VERSION 5.8 ;
BUSBITCHARS "[]" ;
DIVIDERCHAR "/" ;
UNITS
  DATABASE MICRONS 1000 ;
END UNITS
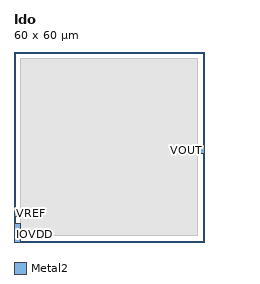
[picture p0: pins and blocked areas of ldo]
MACRO ldo
  CLASS BLOCK ;
  ORIGIN 0 0 ;
  FOREIGN ldo 0 0 ;
  SIZE 60.000 BY 60.000 ;
  SYMMETRY X Y R90 ;
  PIN IOVDD  DIRECTION INOUT ; USE POWER  ; PORT LAYER Metal2 ; RECT 0 0 2 2 ; END END IOVDD
  PIN VSS    DIRECTION INOUT ; USE GROUND ; PORT LAYER Metal2 ; RECT 0 4 2 6 ; END END VSS
  PIN VREF   DIRECTION INPUT ; USE SIGNAL ; PORT LAYER Metal2 ; RECT 0 8 2 10 ; END END VREF
  PIN VOUT   DIRECTION OUTPUT; USE SIGNAL ; PORT LAYER Metal2 ; RECT 58 28 60 30 ; END END VOUT
  OBS LAYER Metal1 ; RECT 2 2 58 58 ; END
END ldo
END LIBRARY
